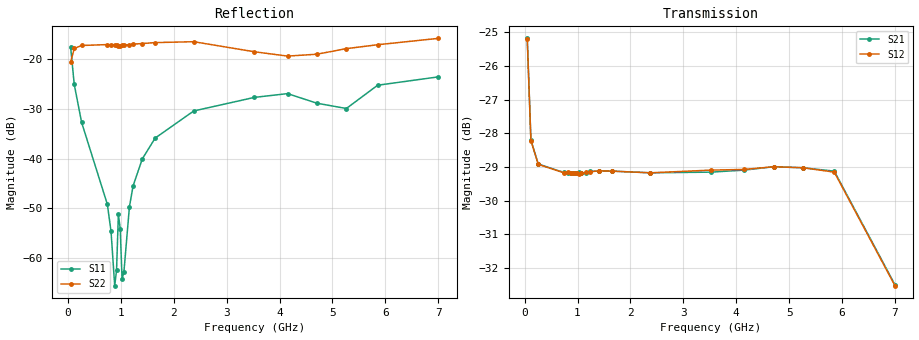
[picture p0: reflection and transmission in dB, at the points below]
! Integrated Device Technology
! Corporate Headquarters
! 6024 Silver Creek Valley Road
! San Jose, CA 95138  USA
! Phone:  1-408-284-8200
! Toll Free:  1-800-223-1366
! Webpage:  http://www.idt.com/
! Timing and RF Division
! 515 Groton Road, Suite 102
! Westford, MA 01886-6024
! Device:  F2258
! Description: Voltage Variable RF Attenuator
! Frequency:  50.0 -  6000.00 MHz
! Package:  3x3 mm Thin QFN Plastic Package: 16 pin
! Ports:  2 RF, 2 DC
!  Pin  1  = NC
!  Pin  2  = NC
!  Pin  3  = RF2  = Port 2
!  Pin  4  = GND
!  Pin  5  = Vdd
!  Pin  6  = NC
!  Pin  7  = VCTRL
!  Pin  8  = NC
!  Pin  9  = GND
!  Pin 10  = RF1  = Port 1
!  Pin 11  = NC
!  Pin 12  = NC
!  Pin 13  = NC
!  Pin 14  = NC
!  Pin 15  = NC
!  Pin 16  = NC
! Vcntrl:  1.640 Volts
! Vdd:  +3.300 Volts
! Current:  1.159 mA
! Data:  The device was measured on a the F2258 evaluation board which has
!  individual transmission lines to the RF pins.  Data was collected
!  using a calibrated network analyzer.  The evaluation board was
!  de-embedded using a TRL calibration technique.
!  The reference plane is the edge of the package pin.
! Misc:  SN 10
!  Action Tracker AT0285
! Date Measured:  2014-12-10
! Date:  2016-01-13  MJV
! Note:
!  Integrated Device Technology supplies this data as a sample of measured
!  data at the package pin for this product.  Your particular data for this
!  product may vary.
!  Data was taken at 25 degrees C.
!  Integrated Device Technology reserves the right to change this data at anytime.
!Freq_(GHz)  S11M_(dB)  S11P_(deg)  S21M_(dB)  S21P_(deg)  S12M_(dB)  S12P_(deg)  S22M_(dB)  S22P_(deg)
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# GHz S dB R 50
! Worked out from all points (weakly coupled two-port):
!   201 points, 50 MHz to 7 GHz, reference 50 ohm
!   highest |S21| = -25.18 dB at 50 MHz (marker M1); lowest = -32.5 dB at 7 GHz (marker M2)
!   lowest |S11| = -65.5 dB at 884 MHz (marker M3), VSWR 1.00, Z = 49.9 + j0.0049 ohm
!   |S11| at or under -10 dB: start of sweep to end of sweep
!   |S22| runs from -20.7 to -15.9 dB; largest |S21 - S12| = 0.00023
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0.05  -17.53 -109.8  -25.18 -48.7  -25.19 -48.7  -20.69 -36.9
0.1195  -25.13 -104.6  -28.20 -26.2  -28.22 -26.2  -17.90 -10.9
0.2585  -32.74 -107.0  -28.91 -14.6  -28.92 -14.6  -17.30 -6.8
0.745  -49.18 -117.6  -29.16 -10.9  -29.17 -10.9  -17.12 -10.3
0.8145  -54.60 -122.7  -29.18 -11.1  -29.16 -11.1  -17.12 -11.1
0.884  -65.52 174.7  -29.17 -11.4  -29.19 -11.4  -17.16 -12.3
0.91875  -62.44 109.5  -29.18 -11.5  -29.18 -11.5  -17.17 -12.8
0.9535  -51.19 -139.2  -29.18 -11.6  -29.19 -11.6  -17.36 -12.4
0.98825  -54.05 -151.8  -29.17 -11.8  -29.18 -11.8  -17.34 -13.2
1.023  -64.21 -146.7  -29.16 -12.0  -29.20 -11.9  -17.28 -13.7
1.05775  -62.82 -3.4  -29.19 -12.1  -29.19 -12.1  -17.23 -14.0
1.162  -49.69 32.8  -29.17 -12.7  -29.16 -12.7  -17.12 -15.3
1.2315  -45.50 26.6  -29.13 -13.2  -29.14 -13.2  -17.03 -16.1
1.40525  -40.07 24.1  -29.12 -14.6  -29.11 -14.6  -16.91 -17.8
1.6485  -35.89 26.6  -29.12 -16.7  -29.12 -16.7  -16.72 -20.8
2.37825  -30.44 44.5  -29.17 -22.7  -29.17 -22.7  -16.54 -28.4
3.525  -27.72 89.9  -29.15 -33.0  -29.09 -33.0  -18.56 -46.7
4.1505  -26.96 104.2  -29.09 -39.1  -29.07 -39.1  -19.43 -63.4
4.7065  -28.89 94.6  -28.99 -44.7  -28.99 -44.7  -19.05 -73.2
5.2625  -29.95 51.7  -29.02 -51.1  -29.02 -51.0  -17.93 -76.3
5.85325  -25.28 28.1  -29.12 -59.5  -29.15 -59.4  -17.15 -76.4
7  -23.60 83.8  -32.49 -72.5  -32.52 -72.5  -15.87 -132.7
